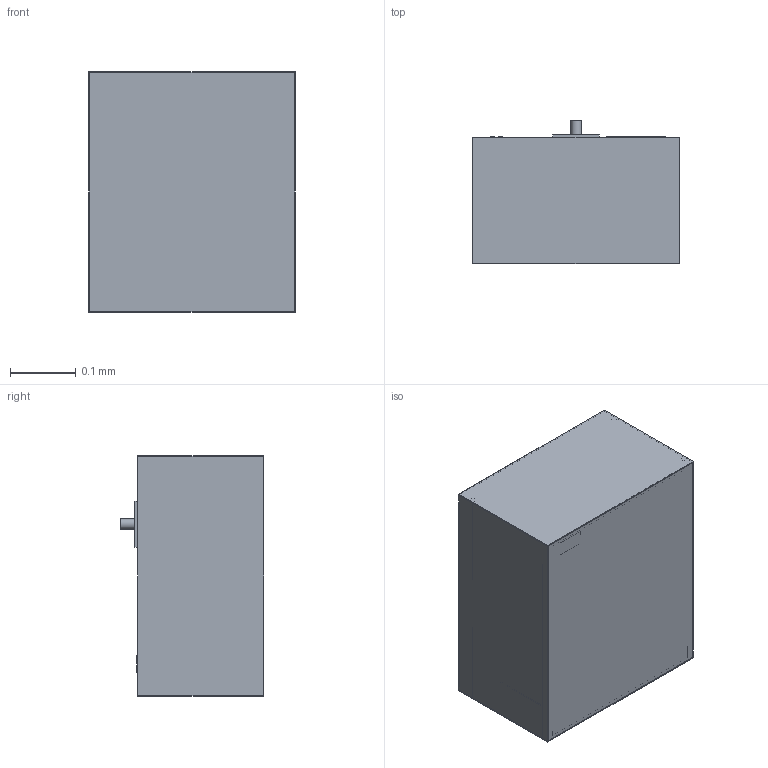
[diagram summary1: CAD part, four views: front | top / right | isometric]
STEP (ISO 10303-21) file: header records copied from the file, then geometry measured from it (millimetres).
FILE_DESCRIPTION(('Open CASCADE Model'),'2;1');
FILE_NAME('Open CASCADE Shape Model','2026-10-04T13:16:05',('Author'),( 'Open CASCADE'),'Open CASCADE STEP processor 7.9','Open CASCADE 7.9' ,'Unknown');
FILE_SCHEMA(('AUTOMOTIVE_DESIGN { 1 0 10303 214 1 1 1 1 }'));
Length unit declared in the file: millimetre
Products named in the file (128): MOD-stem-cell-organoids; fluid__fresh_medium_175_mL; fluid__fresh_medium_port; fluid__4_PFA_175_mL; fluid__4_PFA_port; fluid__PBS_storage_buffer_175_mL; fluid__PBS_storage_buffer_port; fluid__RNA_stabilizer_175_mL; fluid__RNA_stabilizer_port; fluid__waste_bag_empty_at_launch_351_mL_capacity_under_the_reagent_
bags; fluid__waste_bag_port; electronics__controller_enclosure_boards_data_storage; electronics__connector_1; electronics__connector_2; pump__fluid_manifold; pump__micro_pump_1; pump__micro_pump_2; pump__manifold_inlet; pump__manifold_outlet; pump__fluid_manifold_; pump__valve_1; pump__valve_2; pump__valve_3; pump__valve_4; pump__manifold_inlet_; pump__manifold_outlet_; imaging__microscope_base_optics_filter_cubes_camera; imaging__objective; imaging__stage_post_1; imaging__stage_post_2; imaging__stage_post_3; imaging__stage_post_4; imaging__XY_stage_frame_travel_96_5_x_57_9_mm_every_well_over_the_
objective; imaging__stage_carriage; imaging__X_stepper; imaging__Y_stepper; imaging__illumination_column; imaging__illumination_arm; imaging__arm_to_head; imaging__LED_head_transmitted_light ...
Assembly tree (127 placements, depth 2):
  MOD-stem-cell-organoids
    fluid__fresh_medium_175_mL
    fluid__fresh_medium_port
    fluid__4_PFA_175_mL
    fluid__4_PFA_port
    fluid__PBS_storage_buffer_175_mL
    fluid__PBS_storage_buffer_port
    fluid__RNA_stabilizer_175_mL
    fluid__RNA_stabilizer_port
    fluid__waste_bag_empty_at_launch_351_mL_capacity_under_the_reagent_
bags
    fluid__waste_bag_port
    electronics__controller_enclosure_boards_data_storage
    electronics__connector_1
    electronics__connector_2
    pump__fluid_manifold
    pump__micro_pump_1
    pump__micro_pump_2
    pump__manifold_inlet
    pump__manifold_outlet
    pump__fluid_manifold_
    pump__valve_1
    pump__valve_2
    pump__valve_3
    pump__valve_4
    pump__manifold_inlet_
    pump__manifold_outlet_
    imaging__microscope_base_optics_filter_cubes_camera
    imaging__objective
    imaging__stage_post_1
    imaging__stage_post_2
    imaging__stage_post_3
    imaging__stage_post_4
    imaging__XY_stage_frame_travel_96_5_x_57_9_mm_every_well_over_the_
objective
    imaging__stage_carriage
    imaging__X_stepper
    imaging__Y_stepper
    imaging__illumination_column
    imaging__illumination_arm
    imaging__arm_to_head
    imaging__LED_head_transmitted_light
    sample__cassette_24_wells_SBS_footprint_19_3_mm_pitch
    sample__culture_in_the_wells
    sample__cassette_lid_sealed_and_gas_permeable
    sample__cassette_fluid_port_1
    sample__cassette_fluid_port_2
    housing__bottom_panel
    housing__top_panel
    housing__side_panel_L
    housing__side_panel_R
    housing__back_panel_bay_interface
    housing__front_panel
    housing__corner_post_1
    housing__corner_post_2
    housing__corner_post_3
    housing__corner_post_4
    housing__shelf_1
    thermal__cold_wall_to_the_bay_s_thermoelectric_block
    interface__blind_mate_connector_power_data_video
    interface__grapple_fixture_base_Dexter_L
    interface__grapple_fixture_pin
Bounding box: 0.31 x 0.22 x 0.37 mm (x, y, z)
Volume: 0 mm3; surface area: 1.9 mm2
Topology: 151 solids, 151 shells, 628 faces, 906 edges, 604 vertices
Faces by surface type: plane 466, cylinder 162
Full cylindrical faces by diameter (mm): 0.003 x48, 0.005 x27, 0.006 x4, 0.009 x4, 0.01 x4, 0.012 x2, 0.015 x24, 0.016 x25, 0.02 x2, 0.022 x1, 0.028 x1
Entity records: 28598 total; most frequent: DIRECTION 4534, CARTESIAN_POINT 4198, LINE 2070, VECTOR 2070, ORIENTED_EDGE 1812, PCURVE 1812, DEFINITIONAL_REPRESENTATION 1812, AXIS2_PLACEMENT_3D 1080
One B-rep face of a CAD part: STEP entity #18205.
In plain terms, the planar face has unit normal (0, -1, 0).
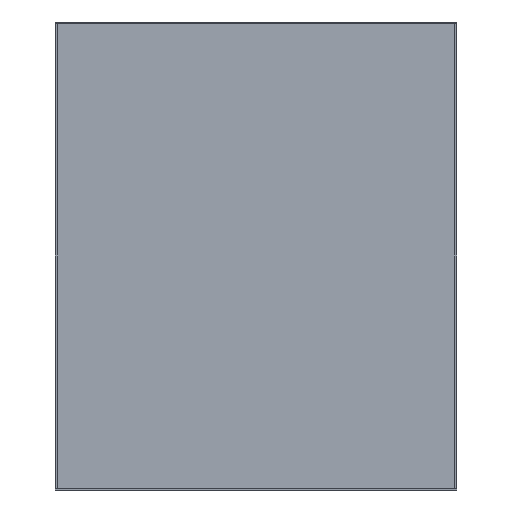
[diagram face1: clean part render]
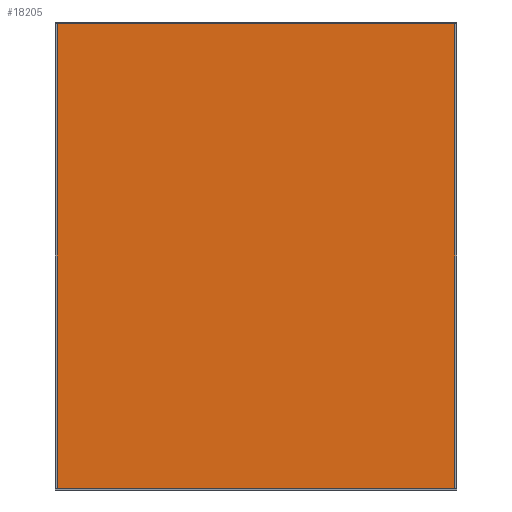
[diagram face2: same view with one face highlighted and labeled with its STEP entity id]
Its self-contained STEP definition (entity closure, numbers rounded to 3 decimals):
#17989 = EDGE_CURVE('',#17990,#17992,#17994,.T.);
#17990 = VERTEX_POINT('',#17991);
#17991 = CARTESIAN_POINT('',(-0.155,-0.096,0.002)
  );
#17992 = VERTEX_POINT('',#17993);
#17993 = CARTESIAN_POINT('',(-0.155,-0.096,
    0.364));
#17994 = SURFACE_CURVE('',#17995,(#17999,#18011),.PCURVE_S1.);
#17995 = LINE('',#17996,#17997);
#17996 = CARTESIAN_POINT('',(-0.155,-0.096,0.002)
  );
#17997 = VECTOR('',#17998,1.);
#17998 = DIRECTION('',(0.,0.,1.));
#17999 = PCURVE('',#18000,#18005);
#18000 = PLANE('',#18001);
#18001 = AXIS2_PLACEMENT_3D('',#18002,#18003,#18004);
#18002 = CARTESIAN_POINT('',(-0.155,-0.096,0.002)
  );
#18003 = DIRECTION('',(1.,0.,0.));
#18004 = DIRECTION('',(0.,0.,1.));
#18005 = DEFINITIONAL_REPRESENTATION('',(#18006),#18010);
#18006 = LINE('',#18007,#18008);
#18007 = CARTESIAN_POINT('',(0.,0.));
#18008 = VECTOR('',#18009,1.);
#18009 = DIRECTION('',(1.,0.));
#18010 = ( GEOMETRIC_REPRESENTATION_CONTEXT(2) 
PARAMETRIC_REPRESENTATION_CONTEXT() REPRESENTATION_CONTEXT('2D SPACE',''
  ) );
#18011 = PCURVE('',#18012,#18017);
#18012 = PLANE('',#18013);
#18013 = AXIS2_PLACEMENT_3D('',#18014,#18015,#18016);
#18014 = CARTESIAN_POINT('',(-0.155,-0.096,0.002)
  );
#18015 = DIRECTION('',(0.,1.,0.));
#18016 = DIRECTION('',(0.,0.,1.));
#18017 = DEFINITIONAL_REPRESENTATION('',(#18018),#18022);
#18018 = LINE('',#18019,#18020);
#18019 = CARTESIAN_POINT('',(0.,0.));
#18020 = VECTOR('',#18021,1.);
#18021 = DIRECTION('',(1.,0.));
#18022 = ( GEOMETRIC_REPRESENTATION_CONTEXT(2) 
PARAMETRIC_REPRESENTATION_CONTEXT() REPRESENTATION_CONTEXT('2D SPACE',''
  ) );
#18040 = PLANE('',#18041);
#18041 = AXIS2_PLACEMENT_3D('',#18042,#18043,#18044);
#18042 = CARTESIAN_POINT('',(-0.155,-0.096,0.002)
  );
#18043 = DIRECTION('',(0.,0.,1.));
#18044 = DIRECTION('',(1.,0.,0.));
#18094 = PLANE('',#18095);
#18095 = AXIS2_PLACEMENT_3D('',#18096,#18097,#18098);
#18096 = CARTESIAN_POINT('',(-0.155,-0.096,
    0.364));
#18097 = DIRECTION('',(0.,0.,1.));
#18098 = DIRECTION('',(1.,0.,0.));
#18109 = EDGE_CURVE('',#18110,#18112,#18114,.T.);
#18110 = VERTEX_POINT('',#18111);
#18111 = CARTESIAN_POINT('',(0.155,-0.096,0.002)
  );
#18112 = VERTEX_POINT('',#18113);
#18113 = CARTESIAN_POINT('',(0.155,-0.096,
    0.364));
#18114 = SURFACE_CURVE('',#18115,(#18119,#18131),.PCURVE_S1.);
#18115 = LINE('',#18116,#18117);
#18116 = CARTESIAN_POINT('',(0.155,-0.096,0.002)
  );
#18117 = VECTOR('',#18118,1.);
#18118 = DIRECTION('',(0.,0.,1.));
#18119 = PCURVE('',#18120,#18125);
#18120 = PLANE('',#18121);
#18121 = AXIS2_PLACEMENT_3D('',#18122,#18123,#18124);
#18122 = CARTESIAN_POINT('',(0.155,-0.096,0.002)
  );
#18123 = DIRECTION('',(1.,0.,0.));
#18124 = DIRECTION('',(0.,0.,1.));
#18125 = DEFINITIONAL_REPRESENTATION('',(#18126),#18130);
#18126 = LINE('',#18127,#18128);
#18127 = CARTESIAN_POINT('',(0.,0.));
#18128 = VECTOR('',#18129,1.);
#18129 = DIRECTION('',(1.,0.));
#18130 = ( GEOMETRIC_REPRESENTATION_CONTEXT(2) 
PARAMETRIC_REPRESENTATION_CONTEXT() REPRESENTATION_CONTEXT('2D SPACE',''
  ) );
#18131 = PCURVE('',#18012,#18132);
#18132 = DEFINITIONAL_REPRESENTATION('',(#18133),#18137);
#18133 = LINE('',#18134,#18135);
#18134 = CARTESIAN_POINT('',(0.,0.31));
#18135 = VECTOR('',#18136,1.);
#18136 = DIRECTION('',(1.,0.));
#18137 = ( GEOMETRIC_REPRESENTATION_CONTEXT(2) 
PARAMETRIC_REPRESENTATION_CONTEXT() REPRESENTATION_CONTEXT('2D SPACE',''
  ) );
#18205 = ADVANCED_FACE('',(#18206),#18012,.F.);
#18206 = FACE_BOUND('',#18207,.F.);
#18207 = EDGE_LOOP('',(#18208,#18229,#18230,#18251));
#18208 = ORIENTED_EDGE('',*,*,#18209,.F.);
#18209 = EDGE_CURVE('',#17990,#18110,#18210,.T.);
#18210 = SURFACE_CURVE('',#18211,(#18215,#18222),.PCURVE_S1.);
#18211 = LINE('',#18212,#18213);
#18212 = CARTESIAN_POINT('',(-0.155,-0.096,0.002)
  );
#18213 = VECTOR('',#18214,1.);
#18214 = DIRECTION('',(1.,0.,0.));
#18215 = PCURVE('',#18012,#18216);
#18216 = DEFINITIONAL_REPRESENTATION('',(#18217),#18221);
#18217 = LINE('',#18218,#18219);
#18218 = CARTESIAN_POINT('',(0.,0.));
#18219 = VECTOR('',#18220,1.);
#18220 = DIRECTION('',(0.,1.));
#18221 = ( GEOMETRIC_REPRESENTATION_CONTEXT(2) 
PARAMETRIC_REPRESENTATION_CONTEXT() REPRESENTATION_CONTEXT('2D SPACE',''
  ) );
#18222 = PCURVE('',#18040,#18223);
#18223 = DEFINITIONAL_REPRESENTATION('',(#18224),#18228);
#18224 = LINE('',#18225,#18226);
#18225 = CARTESIAN_POINT('',(0.,0.));
#18226 = VECTOR('',#18227,1.);
#18227 = DIRECTION('',(1.,0.));
#18228 = ( GEOMETRIC_REPRESENTATION_CONTEXT(2) 
PARAMETRIC_REPRESENTATION_CONTEXT() REPRESENTATION_CONTEXT('2D SPACE',''
  ) );
#18229 = ORIENTED_EDGE('',*,*,#17989,.T.);
#18230 = ORIENTED_EDGE('',*,*,#18231,.T.);
#18231 = EDGE_CURVE('',#17992,#18112,#18232,.T.);
#18232 = SURFACE_CURVE('',#18233,(#18237,#18244),.PCURVE_S1.);
#18233 = LINE('',#18234,#18235);
#18234 = CARTESIAN_POINT('',(-0.155,-0.096,
    0.364));
#18235 = VECTOR('',#18236,1.);
#18236 = DIRECTION('',(1.,0.,0.));
#18237 = PCURVE('',#18012,#18238);
#18238 = DEFINITIONAL_REPRESENTATION('',(#18239),#18243);
#18239 = LINE('',#18240,#18241);
#18240 = CARTESIAN_POINT('',(0.362,0.));
#18241 = VECTOR('',#18242,1.);
#18242 = DIRECTION('',(0.,1.));
#18243 = ( GEOMETRIC_REPRESENTATION_CONTEXT(2) 
PARAMETRIC_REPRESENTATION_CONTEXT() REPRESENTATION_CONTEXT('2D SPACE',''
  ) );
#18244 = PCURVE('',#18094,#18245);
#18245 = DEFINITIONAL_REPRESENTATION('',(#18246),#18250);
#18246 = LINE('',#18247,#18248);
#18247 = CARTESIAN_POINT('',(0.,0.));
#18248 = VECTOR('',#18249,1.);
#18249 = DIRECTION('',(1.,0.));
#18250 = ( GEOMETRIC_REPRESENTATION_CONTEXT(2) 
PARAMETRIC_REPRESENTATION_CONTEXT() REPRESENTATION_CONTEXT('2D SPACE',''
  ) );
#18251 = ORIENTED_EDGE('',*,*,#18109,.F.);
